# Generated deterministically by seda-macro-lef-normalizer-v1; recipe orfs-ng45-fakeram-metal3-coupledl2-pg-v1.
VERSION 5.8 ;
BUSBITCHARS "[]" ;
DIVIDERCHAR "/" ;

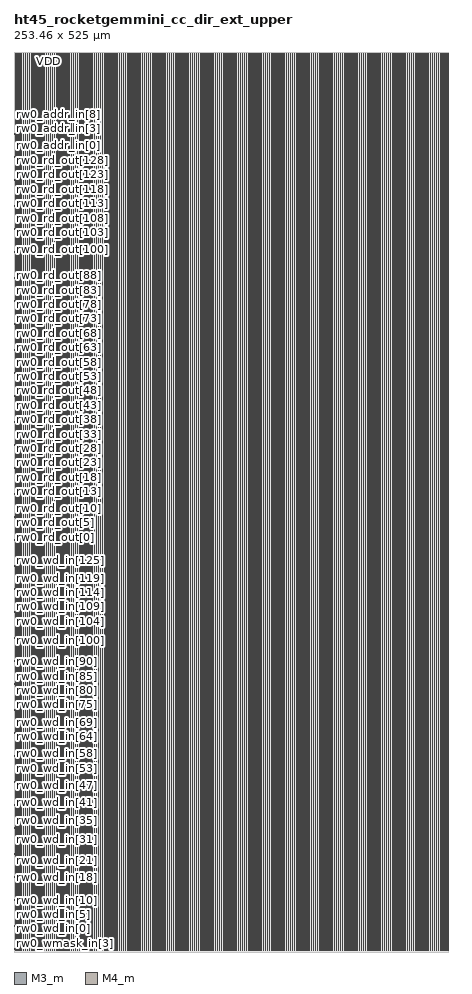
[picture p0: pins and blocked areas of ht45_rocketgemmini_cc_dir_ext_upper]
MACRO ht45_rocketgemmini_cc_dir_ext_upper
  FOREIGN ht45_rocketgemmini_cc_dir_ext_upper 0 0 ;
  CLASS COVER ;
  ORIGIN 0 0 ;
  SIZE 253.46 BY 525 ;
  SYMMETRY X Y R90 ;
  PIN rw0_wmask_in[0]
    DIRECTION INPUT ;
    USE SIGNAL ;
    SHAPE ABUTMENT ;
    PORT
      LAYER M3_m ;
      RECT 0 0.035 0.07 0.105 ;
    END
  END rw0_wmask_in[0]
  PIN rw0_wmask_in[1]
    DIRECTION INPUT ;
    USE SIGNAL ;
    SHAPE ABUTMENT ;
    PORT
      LAYER M3_m ;
      RECT 0 1.715 0.07 1.785 ;
    END
  END rw0_wmask_in[1]
  PIN rw0_wmask_in[2]
    DIRECTION INPUT ;
    USE SIGNAL ;
    SHAPE ABUTMENT ;
    PORT
      LAYER M3_m ;
      RECT 0 3.395 0.07 3.465 ;
    END
  END rw0_wmask_in[2]
  PIN rw0_wmask_in[3]
    DIRECTION INPUT ;
    USE SIGNAL ;
    SHAPE ABUTMENT ;
    PORT
      LAYER M3_m ;
      RECT 0 5.075 0.07 5.145 ;
    END
  END rw0_wmask_in[3]
  PIN rw0_wmask_in[4]
    DIRECTION INPUT ;
    USE SIGNAL ;
    SHAPE ABUTMENT ;
    PORT
      LAYER M3_m ;
      RECT 0 6.755 0.07 6.825 ;
    END
  END rw0_wmask_in[4]
  PIN rw0_wmask_in[5]
    DIRECTION INPUT ;
    USE SIGNAL ;
    SHAPE ABUTMENT ;
    PORT
      LAYER M3_m ;
      RECT 0 8.435 0.07 8.505 ;
    END
  END rw0_wmask_in[5]
  PIN rw0_wmask_in[6]
    DIRECTION INPUT ;
    USE SIGNAL ;
    SHAPE ABUTMENT ;
    PORT
      LAYER M3_m ;
      RECT 0 10.115 0.07 10.185 ;
    END
  END rw0_wmask_in[6]
  PIN rw0_wmask_in[7]
    DIRECTION INPUT ;
    USE SIGNAL ;
    SHAPE ABUTMENT ;
    PORT
      LAYER M3_m ;
      RECT 0 11.795 0.07 11.865 ;
    END
  END rw0_wmask_in[7]
  PIN rw0_wd_in[0]
    DIRECTION INPUT ;
    USE SIGNAL ;
    SHAPE ABUTMENT ;
    PORT
      LAYER M3_m ;
      RECT 0 13.475 0.07 13.545 ;
    END
  END rw0_wd_in[0]
  PIN rw0_wd_in[1]
    DIRECTION INPUT ;
    USE SIGNAL ;
    SHAPE ABUTMENT ;
    PORT
      LAYER M3_m ;
      RECT 0 15.155 0.07 15.225 ;
    END
  END rw0_wd_in[1]
  PIN rw0_wd_in[2]
    DIRECTION INPUT ;
    USE SIGNAL ;
    SHAPE ABUTMENT ;
    PORT
      LAYER M3_m ;
      RECT 0 16.835 0.07 16.905 ;
    END
  END rw0_wd_in[2]
  PIN rw0_wd_in[3]
    DIRECTION INPUT ;
    USE SIGNAL ;
    SHAPE ABUTMENT ;
    PORT
      LAYER M3_m ;
      RECT 0 18.515 0.07 18.585 ;
    END
  END rw0_wd_in[3]
  PIN rw0_wd_in[4]
    DIRECTION INPUT ;
    USE SIGNAL ;
    SHAPE ABUTMENT ;
    PORT
      LAYER M3_m ;
      RECT 0 20.195 0.07 20.265 ;
    END
  END rw0_wd_in[4]
  PIN rw0_wd_in[5]
    DIRECTION INPUT ;
    USE SIGNAL ;
    SHAPE ABUTMENT ;
    PORT
      LAYER M3_m ;
      RECT 0 21.875 0.07 21.945 ;
    END
  END rw0_wd_in[5]
  PIN rw0_wd_in[6]
    DIRECTION INPUT ;
    USE SIGNAL ;
    SHAPE ABUTMENT ;
    PORT
      LAYER M3_m ;
      RECT 0 23.555 0.07 23.625 ;
    END
  END rw0_wd_in[6]
  PIN rw0_wd_in[7]
    DIRECTION INPUT ;
    USE SIGNAL ;
    SHAPE ABUTMENT ;
    PORT
      LAYER M3_m ;
      RECT 0 25.235 0.07 25.305 ;
    END
  END rw0_wd_in[7]
  PIN rw0_wd_in[8]
    DIRECTION INPUT ;
    USE SIGNAL ;
    SHAPE ABUTMENT ;
    PORT
      LAYER M3_m ;
      RECT 0 26.915 0.07 26.985 ;
    END
  END rw0_wd_in[8]
  PIN rw0_wd_in[9]
    DIRECTION INPUT ;
    USE SIGNAL ;
    SHAPE ABUTMENT ;
    PORT
      LAYER M3_m ;
      RECT 0 28.595 0.07 28.665 ;
    END
  END rw0_wd_in[9]
  PIN rw0_wd_in[10]
    DIRECTION INPUT ;
    USE SIGNAL ;
    SHAPE ABUTMENT ;
    PORT
      LAYER M3_m ;
      RECT 0 30.275 0.07 30.345 ;
    END
  END rw0_wd_in[10]
  PIN rw0_wd_in[11]
    DIRECTION INPUT ;
    USE SIGNAL ;
    SHAPE ABUTMENT ;
    PORT
      LAYER M3_m ;
      RECT 0 31.955 0.07 32.025 ;
    END
  END rw0_wd_in[11]
  PIN rw0_wd_in[12]
    DIRECTION INPUT ;
    USE SIGNAL ;
    SHAPE ABUTMENT ;
    PORT
      LAYER M3_m ;
      RECT 0 33.635 0.07 33.705 ;
    END
  END rw0_wd_in[12]
  PIN rw0_wd_in[13]
    DIRECTION INPUT ;
    USE SIGNAL ;
    SHAPE ABUTMENT ;
    PORT
      LAYER M3_m ;
      RECT 0 35.315 0.07 35.385 ;
    END
  END rw0_wd_in[13]
  PIN rw0_wd_in[14]
    DIRECTION INPUT ;
    USE SIGNAL ;
    SHAPE ABUTMENT ;
    PORT
      LAYER M3_m ;
      RECT 0 36.995 0.07 37.065 ;
    END
  END rw0_wd_in[14]
  PIN rw0_wd_in[15]
    DIRECTION INPUT ;
    USE SIGNAL ;
    SHAPE ABUTMENT ;
    PORT
      LAYER M3_m ;
      RECT 0 38.675 0.07 38.745 ;
    END
  END rw0_wd_in[15]
  PIN rw0_wd_in[16]
    DIRECTION INPUT ;
    USE SIGNAL ;
    SHAPE ABUTMENT ;
    PORT
      LAYER M3_m ;
      RECT 0 40.355 0.07 40.425 ;
    END
  END rw0_wd_in[16]
  PIN rw0_wd_in[17]
    DIRECTION INPUT ;
    USE SIGNAL ;
    SHAPE ABUTMENT ;
    PORT
      LAYER M3_m ;
      RECT 0 42.035 0.07 42.105 ;
    END
  END rw0_wd_in[17]
  PIN rw0_wd_in[18]
    DIRECTION INPUT ;
    USE SIGNAL ;
    SHAPE ABUTMENT ;
    PORT
      LAYER M3_m ;
      RECT 0 43.715 0.07 43.785 ;
    END
  END rw0_wd_in[18]
  PIN rw0_wd_in[19]
    DIRECTION INPUT ;
    USE SIGNAL ;
    SHAPE ABUTMENT ;
    PORT
      LAYER M3_m ;
      RECT 0 45.395 0.07 45.465 ;
    END
  END rw0_wd_in[19]
  PIN rw0_wd_in[20]
    DIRECTION INPUT ;
    USE SIGNAL ;
    SHAPE ABUTMENT ;
    PORT
      LAYER M3_m ;
      RECT 0 47.075 0.07 47.145 ;
    END
  END rw0_wd_in[20]
  PIN rw0_wd_in[21]
    DIRECTION INPUT ;
    USE SIGNAL ;
    SHAPE ABUTMENT ;
    PORT
      LAYER M3_m ;
      RECT 0 48.755 0.07 48.825 ;
    END
  END rw0_wd_in[21]
  PIN rw0_wd_in[22]
    DIRECTION INPUT ;
    USE SIGNAL ;
    SHAPE ABUTMENT ;
    PORT
      LAYER M3_m ;
      RECT 0 50.435 0.07 50.505 ;
    END
  END rw0_wd_in[22]
  PIN rw0_wd_in[23]
    DIRECTION INPUT ;
    USE SIGNAL ;
    SHAPE ABUTMENT ;
    PORT
      LAYER M3_m ;
      RECT 0 52.115 0.07 52.185 ;
    END
  END rw0_wd_in[23]
  PIN rw0_wd_in[24]
    DIRECTION INPUT ;
    USE SIGNAL ;
    SHAPE ABUTMENT ;
    PORT
      LAYER M3_m ;
      RECT 0 53.795 0.07 53.865 ;
    END
  END rw0_wd_in[24]
  PIN rw0_wd_in[25]
    DIRECTION INPUT ;
    USE SIGNAL ;
    SHAPE ABUTMENT ;
    PORT
      LAYER M3_m ;
      RECT 0 55.475 0.07 55.545 ;
    END
  END rw0_wd_in[25]
  PIN rw0_wd_in[26]
    DIRECTION INPUT ;
    USE SIGNAL ;
    SHAPE ABUTMENT ;
    PORT
      LAYER M3_m ;
      RECT 0 57.155 0.07 57.225 ;
    END
  END rw0_wd_in[26]
  PIN rw0_wd_in[27]
    DIRECTION INPUT ;
    USE SIGNAL ;
    SHAPE ABUTMENT ;
    PORT
      LAYER M3_m ;
      RECT 0 58.835 0.07 58.905 ;
    END
  END rw0_wd_in[27]
  PIN rw0_wd_in[28]
    DIRECTION INPUT ;
    USE SIGNAL ;
    SHAPE ABUTMENT ;
    PORT
      LAYER M3_m ;
      RECT 0 60.515 0.07 60.585 ;
    END
  END rw0_wd_in[28]
  PIN rw0_wd_in[29]
    DIRECTION INPUT ;
    USE SIGNAL ;
    SHAPE ABUTMENT ;
    PORT
      LAYER M3_m ;
      RECT 0 62.195 0.07 62.265 ;
    END
  END rw0_wd_in[29]
  PIN rw0_wd_in[30]
    DIRECTION INPUT ;
    USE SIGNAL ;
    SHAPE ABUTMENT ;
    PORT
      LAYER M3_m ;
      RECT 0 63.875 0.07 63.945 ;
    END
  END rw0_wd_in[30]
  PIN rw0_wd_in[31]
    DIRECTION INPUT ;
    USE SIGNAL ;
    SHAPE ABUTMENT ;
    PORT
      LAYER M3_m ;
      RECT 0 65.555 0.07 65.625 ;
    END
  END rw0_wd_in[31]
  PIN rw0_wd_in[32]
    DIRECTION INPUT ;
    USE SIGNAL ;
    SHAPE ABUTMENT ;
    PORT
      LAYER M3_m ;
      RECT 0 67.235 0.07 67.305 ;
    END
  END rw0_wd_in[32]
  PIN rw0_wd_in[33]
    DIRECTION INPUT ;
    USE SIGNAL ;
    SHAPE ABUTMENT ;
    PORT
      LAYER M3_m ;
      RECT 0 68.915 0.07 68.985 ;
    END
  END rw0_wd_in[33]
  PIN rw0_wd_in[34]
    DIRECTION INPUT ;
    USE SIGNAL ;
    SHAPE ABUTMENT ;
    PORT
      LAYER M3_m ;
      RECT 0 70.595 0.07 70.665 ;
    END
  END rw0_wd_in[34]
  PIN rw0_wd_in[35]
    DIRECTION INPUT ;
    USE SIGNAL ;
    SHAPE ABUTMENT ;
    PORT
      LAYER M3_m ;
      RECT 0 72.275 0.07 72.345 ;
    END
  END rw0_wd_in[35]
  PIN rw0_wd_in[36]
    DIRECTION INPUT ;
    USE SIGNAL ;
    SHAPE ABUTMENT ;
    PORT
      LAYER M3_m ;
      RECT 0 73.955 0.07 74.025 ;
    END
  END rw0_wd_in[36]
  PIN rw0_wd_in[37]
    DIRECTION INPUT ;
    USE SIGNAL ;
    SHAPE ABUTMENT ;
    PORT
      LAYER M3_m ;
      RECT 0 75.635 0.07 75.705 ;
    END
  END rw0_wd_in[37]
  PIN rw0_wd_in[38]
    DIRECTION INPUT ;
    USE SIGNAL ;
    SHAPE ABUTMENT ;
    PORT
      LAYER M3_m ;
      RECT 0 77.315 0.07 77.385 ;
    END
  END rw0_wd_in[38]
  PIN rw0_wd_in[39]
    DIRECTION INPUT ;
    USE SIGNAL ;
    SHAPE ABUTMENT ;
    PORT
      LAYER M3_m ;
      RECT 0 78.995 0.07 79.065 ;
    END
  END rw0_wd_in[39]
  PIN rw0_wd_in[40]
    DIRECTION INPUT ;
    USE SIGNAL ;
    SHAPE ABUTMENT ;
    PORT
      LAYER M3_m ;
      RECT 0 80.675 0.07 80.745 ;
    END
  END rw0_wd_in[40]
  PIN rw0_wd_in[41]
    DIRECTION INPUT ;
    USE SIGNAL ;
    SHAPE ABUTMENT ;
    PORT
      LAYER M3_m ;
      RECT 0 82.355 0.07 82.425 ;
    END
  END rw0_wd_in[41]
  PIN rw0_wd_in[42]
    DIRECTION INPUT ;
    USE SIGNAL ;
    SHAPE ABUTMENT ;
    PORT
      LAYER M3_m ;
      RECT 0 84.035 0.07 84.105 ;
    END
  END rw0_wd_in[42]
  PIN rw0_wd_in[43]
    DIRECTION INPUT ;
    USE SIGNAL ;
    SHAPE ABUTMENT ;
    PORT
      LAYER M3_m ;
      RECT 0 85.715 0.07 85.785 ;
    END
  END rw0_wd_in[43]
  PIN rw0_wd_in[44]
    DIRECTION INPUT ;
    USE SIGNAL ;
    SHAPE ABUTMENT ;
    PORT
      LAYER M3_m ;
      RECT 0 87.395 0.07 87.465 ;
    END
  END rw0_wd_in[44]
  PIN rw0_wd_in[45]
    DIRECTION INPUT ;
    USE SIGNAL ;
    SHAPE ABUTMENT ;
    PORT
      LAYER M3_m ;
      RECT 0 89.075 0.07 89.145 ;
    END
  END rw0_wd_in[45]
  PIN rw0_wd_in[46]
    DIRECTION INPUT ;
    USE SIGNAL ;
    SHAPE ABUTMENT ;
    PORT
      LAYER M3_m ;
      RECT 0 90.755 0.07 90.825 ;
    END
  END rw0_wd_in[46]
  PIN rw0_wd_in[47]
    DIRECTION INPUT ;
    USE SIGNAL ;
    SHAPE ABUTMENT ;
    PORT
      LAYER M3_m ;
      RECT 0 92.435 0.07 92.505 ;
    END
  END rw0_wd_in[47]
  PIN rw0_wd_in[48]
    DIRECTION INPUT ;
    USE SIGNAL ;
    SHAPE ABUTMENT ;
    PORT
      LAYER M3_m ;
      RECT 0 94.115 0.07 94.185 ;
    END
  END rw0_wd_in[48]
  PIN rw0_wd_in[49]
    DIRECTION INPUT ;
    USE SIGNAL ;
    SHAPE ABUTMENT ;
    PORT
      LAYER M3_m ;
      RECT 0 95.795 0.07 95.865 ;
    END
  END rw0_wd_in[49]
  PIN rw0_wd_in[50]
    DIRECTION INPUT ;
    USE SIGNAL ;
    SHAPE ABUTMENT ;
    PORT
      LAYER M3_m ;
      RECT 0 97.475 0.07 97.545 ;
    END
  END rw0_wd_in[50]
  PIN rw0_wd_in[51]
    DIRECTION INPUT ;
    USE SIGNAL ;
    SHAPE ABUTMENT ;
    PORT
      LAYER M3_m ;
      RECT 0 99.155 0.07 99.225 ;
    END
  END rw0_wd_in[51]
  PIN rw0_wd_in[52]
    DIRECTION INPUT ;
    USE SIGNAL ;
    SHAPE ABUTMENT ;
    PORT
      LAYER M3_m ;
      RECT 0 100.835 0.07 100.905 ;
    END
  END rw0_wd_in[52]
  PIN rw0_wd_in[53]
    DIRECTION INPUT ;
    USE SIGNAL ;
    SHAPE ABUTMENT ;
    PORT
      LAYER M3_m ;
      RECT 0 102.515 0.07 102.585 ;
    END
  END rw0_wd_in[53]
  PIN rw0_wd_in[54]
    DIRECTION INPUT ;
    USE SIGNAL ;
    SHAPE ABUTMENT ;
    PORT
      LAYER M3_m ;
      RECT 0 104.195 0.07 104.265 ;
    END
  END rw0_wd_in[54]
  PIN rw0_wd_in[55]
    DIRECTION INPUT ;
    USE SIGNAL ;
    SHAPE ABUTMENT ;
    PORT
      LAYER M3_m ;
      RECT 0 105.875 0.07 105.945 ;
    END
  END rw0_wd_in[55]
  PIN rw0_wd_in[56]
    DIRECTION INPUT ;
    USE SIGNAL ;
    SHAPE ABUTMENT ;
    PORT
      LAYER M3_m ;
      RECT 0 107.555 0.07 107.625 ;
    END
  END rw0_wd_in[56]
  PIN rw0_wd_in[57]
    DIRECTION INPUT ;
    USE SIGNAL ;
    SHAPE ABUTMENT ;
    PORT
      LAYER M3_m ;
      RECT 0 109.235 0.07 109.305 ;
    END
  END rw0_wd_in[57]
  PIN rw0_wd_in[58]
    DIRECTION INPUT ;
    USE SIGNAL ;
    SHAPE ABUTMENT ;
    PORT
      LAYER M3_m ;
      RECT 0 110.915 0.07 110.985 ;
    END
  END rw0_wd_in[58]
  PIN rw0_wd_in[59]
    DIRECTION INPUT ;
    USE SIGNAL ;
    SHAPE ABUTMENT ;
    PORT
      LAYER M3_m ;
      RECT 0 112.595 0.07 112.665 ;
    END
  END rw0_wd_in[59]
  PIN rw0_wd_in[60]
    DIRECTION INPUT ;
    USE SIGNAL ;
    SHAPE ABUTMENT ;
    PORT
      LAYER M3_m ;
      RECT 0 114.275 0.07 114.345 ;
    END
  END rw0_wd_in[60]
  PIN rw0_wd_in[61]
    DIRECTION INPUT ;
    USE SIGNAL ;
    SHAPE ABUTMENT ;
    PORT
      LAYER M3_m ;
      RECT 0 115.955 0.07 116.025 ;
    END
  END rw0_wd_in[61]
  PIN rw0_wd_in[62]
    DIRECTION INPUT ;
    USE SIGNAL ;
    SHAPE ABUTMENT ;
    PORT
      LAYER M3_m ;
      RECT 0 117.635 0.07 117.705 ;
    END
  END rw0_wd_in[62]
  PIN rw0_wd_in[63]
    DIRECTION INPUT ;
    USE SIGNAL ;
    SHAPE ABUTMENT ;
    PORT
      LAYER M3_m ;
      RECT 0 119.315 0.07 119.385 ;
    END
  END rw0_wd_in[63]
  PIN rw0_wd_in[64]
    DIRECTION INPUT ;
    USE SIGNAL ;
    SHAPE ABUTMENT ;
    PORT
      LAYER M3_m ;
      RECT 0 120.995 0.07 121.065 ;
    END
  END rw0_wd_in[64]
  PIN rw0_wd_in[65]
    DIRECTION INPUT ;
    USE SIGNAL ;
    SHAPE ABUTMENT ;
    PORT
      LAYER M3_m ;
      RECT 0 122.675 0.07 122.745 ;
    END
  END rw0_wd_in[65]
  PIN rw0_wd_in[66]
    DIRECTION INPUT ;
    USE SIGNAL ;
    SHAPE ABUTMENT ;
    PORT
      LAYER M3_m ;
      RECT 0 124.355 0.07 124.425 ;
    END
  END rw0_wd_in[66]
  PIN rw0_wd_in[67]
    DIRECTION INPUT ;
    USE SIGNAL ;
    SHAPE ABUTMENT ;
    PORT
      LAYER M3_m ;
      RECT 0 126.035 0.07 126.105 ;
    END
  END rw0_wd_in[67]
  PIN rw0_wd_in[68]
    DIRECTION INPUT ;
    USE SIGNAL ;
    SHAPE ABUTMENT ;
    PORT
      LAYER M3_m ;
      RECT 0 127.715 0.07 127.785 ;
    END
  END rw0_wd_in[68]
  PIN rw0_wd_in[69]
    DIRECTION INPUT ;
    USE SIGNAL ;
    SHAPE ABUTMENT ;
    PORT
      LAYER M3_m ;
      RECT 0 129.395 0.07 129.465 ;
    END
  END rw0_wd_in[69]
  PIN rw0_wd_in[70]
    DIRECTION INPUT ;
    USE SIGNAL ;
    SHAPE ABUTMENT ;
    PORT
      LAYER M3_m ;
      RECT 0 131.075 0.07 131.145 ;
    END
  END rw0_wd_in[70]
  PIN rw0_wd_in[71]
    DIRECTION INPUT ;
    USE SIGNAL ;
    SHAPE ABUTMENT ;
    PORT
      LAYER M3_m ;
      RECT 0 132.755 0.07 132.825 ;
    END
  END rw0_wd_in[71]
  PIN rw0_wd_in[72]
    DIRECTION INPUT ;
    USE SIGNAL ;
    SHAPE ABUTMENT ;
    PORT
      LAYER M3_m ;
      RECT 0 134.435 0.07 134.505 ;
    END
  END rw0_wd_in[72]
  PIN rw0_wd_in[73]
    DIRECTION INPUT ;
    USE SIGNAL ;
    SHAPE ABUTMENT ;
    PORT
      LAYER M3_m ;
      RECT 0 136.115 0.07 136.185 ;
    END
  END rw0_wd_in[73]
  PIN rw0_wd_in[74]
    DIRECTION INPUT ;
    USE SIGNAL ;
    SHAPE ABUTMENT ;
    PORT
      LAYER M3_m ;
      RECT 0 137.795 0.07 137.865 ;
    END
  END rw0_wd_in[74]
  PIN rw0_wd_in[75]
    DIRECTION INPUT ;
    USE SIGNAL ;
    SHAPE ABUTMENT ;
    PORT
      LAYER M3_m ;
      RECT 0 139.475 0.07 139.545 ;
    END
  END rw0_wd_in[75]
  PIN rw0_wd_in[76]
    DIRECTION INPUT ;
    USE SIGNAL ;
    SHAPE ABUTMENT ;
    PORT
      LAYER M3_m ;
      RECT 0 141.155 0.07 141.225 ;
    END
  END rw0_wd_in[76]
  PIN rw0_wd_in[77]
    DIRECTION INPUT ;
    USE SIGNAL ;
    SHAPE ABUTMENT ;
    PORT
      LAYER M3_m ;
      RECT 0 142.835 0.07 142.905 ;
    END
  END rw0_wd_in[77]
  PIN rw0_wd_in[78]
    DIRECTION INPUT ;
    USE SIGNAL ;
    SHAPE ABUTMENT ;
    PORT
      LAYER M3_m ;
      RECT 0 144.515 0.07 144.585 ;
    END
  END rw0_wd_in[78]
  PIN rw0_wd_in[79]
    DIRECTION INPUT ;
    USE SIGNAL ;
    SHAPE ABUTMENT ;
    PORT
      LAYER M3_m ;
      RECT 0 146.195 0.07 146.265 ;
    END
  END rw0_wd_in[79]
  PIN rw0_wd_in[80]
    DIRECTION INPUT ;
    USE SIGNAL ;
    SHAPE ABUTMENT ;
    PORT
      LAYER M3_m ;
      RECT 0 147.875 0.07 147.945 ;
    END
  END rw0_wd_in[80]
  PIN rw0_wd_in[81]
    DIRECTION INPUT ;
    USE SIGNAL ;
    SHAPE ABUTMENT ;
    PORT
      LAYER M3_m ;
      RECT 0 149.555 0.07 149.625 ;
    END
  END rw0_wd_in[81]
  PIN rw0_wd_in[82]
    DIRECTION INPUT ;
    USE SIGNAL ;
    SHAPE ABUTMENT ;
    PORT
      LAYER M3_m ;
      RECT 0 151.235 0.07 151.305 ;
    END
  END rw0_wd_in[82]
  PIN rw0_wd_in[83]
    DIRECTION INPUT ;
    USE SIGNAL ;
    SHAPE ABUTMENT ;
    PORT
      LAYER M3_m ;
      RECT 0 152.915 0.07 152.985 ;
    END
  END rw0_wd_in[83]
  PIN rw0_wd_in[84]
    DIRECTION INPUT ;
    USE SIGNAL ;
    SHAPE ABUTMENT ;
    PORT
      LAYER M3_m ;
      RECT 0 154.595 0.07 154.665 ;
    END
  END rw0_wd_in[84]
  PIN rw0_wd_in[85]
    DIRECTION INPUT ;
    USE SIGNAL ;
    SHAPE ABUTMENT ;
    PORT
      LAYER M3_m ;
      RECT 0 156.275 0.07 156.345 ;
    END
  END rw0_wd_in[85]
  PIN rw0_wd_in[86]
    DIRECTION INPUT ;
    USE SIGNAL ;
    SHAPE ABUTMENT ;
    PORT
      LAYER M3_m ;
      RECT 0 157.955 0.07 158.025 ;
    END
  END rw0_wd_in[86]
  PIN rw0_wd_in[87]
    DIRECTION INPUT ;
    USE SIGNAL ;
    SHAPE ABUTMENT ;
    PORT
      LAYER M3_m ;
      RECT 0 159.635 0.07 159.705 ;
    END
  END rw0_wd_in[87]
  PIN rw0_wd_in[88]
    DIRECTION INPUT ;
    USE SIGNAL ;
    SHAPE ABUTMENT ;
    PORT
      LAYER M3_m ;
      RECT 0 161.315 0.07 161.385 ;
    END
  END rw0_wd_in[88]
  PIN rw0_wd_in[89]
    DIRECTION INPUT ;
    USE SIGNAL ;
    SHAPE ABUTMENT ;
    PORT
      LAYER M3_m ;
      RECT 0 162.995 0.07 163.065 ;
    END
  END rw0_wd_in[89]
  PIN rw0_wd_in[90]
    DIRECTION INPUT ;
    USE SIGNAL ;
    SHAPE ABUTMENT ;
    PORT
      LAYER M3_m ;
      RECT 0 164.675 0.07 164.745 ;
    END
  END rw0_wd_in[90]
  PIN rw0_wd_in[91]
    DIRECTION INPUT ;
    USE SIGNAL ;
    SHAPE ABUTMENT ;
    PORT
      LAYER M3_m ;
      RECT 0 166.355 0.07 166.425 ;
    END
  END rw0_wd_in[91]
  PIN rw0_wd_in[92]
    DIRECTION INPUT ;
    USE SIGNAL ;
    SHAPE ABUTMENT ;
    PORT
      LAYER M3_m ;
      RECT 0 168.035 0.07 168.105 ;
    END
  END rw0_wd_in[92]
  PIN rw0_wd_in[93]
    DIRECTION INPUT ;
    USE SIGNAL ;
    SHAPE ABUTMENT ;
    PORT
      LAYER M3_m ;
      RECT 0 169.715 0.07 169.785 ;
    END
  END rw0_wd_in[93]
  PIN rw0_wd_in[94]
    DIRECTION INPUT ;
    USE SIGNAL ;
    SHAPE ABUTMENT ;
    PORT
      LAYER M3_m ;
      RECT 0 171.395 0.07 171.465 ;
    END
  END rw0_wd_in[94]
  PIN rw0_wd_in[95]
    DIRECTION INPUT ;
    USE SIGNAL ;
    SHAPE ABUTMENT ;
    PORT
      LAYER M3_m ;
      RECT 0 173.075 0.07 173.145 ;
    END
  END rw0_wd_in[95]
  PIN rw0_wd_in[96]
    DIRECTION INPUT ;
    USE SIGNAL ;
    SHAPE ABUTMENT ;
    PORT
      LAYER M3_m ;
      RECT 0 174.755 0.07 174.825 ;
    END
  END rw0_wd_in[96]
  PIN rw0_wd_in[97]
    DIRECTION INPUT ;
    USE SIGNAL ;
    SHAPE ABUTMENT ;
    PORT
      LAYER M3_m ;
      RECT 0 176.435 0.07 176.505 ;
    END
  END rw0_wd_in[97]
  PIN rw0_wd_in[98]
    DIRECTION INPUT ;
    USE SIGNAL ;
    SHAPE ABUTMENT ;
    PORT
      LAYER M3_m ;
      RECT 0 178.115 0.07 178.185 ;
    END
  END rw0_wd_in[98]
  PIN rw0_wd_in[99]
    DIRECTION INPUT ;
    USE SIGNAL ;
    SHAPE ABUTMENT ;
    PORT
      LAYER M3_m ;
      RECT 0 179.795 0.07 179.865 ;
    END
  END rw0_wd_in[99]
  PIN rw0_wd_in[100]
    DIRECTION INPUT ;
    USE SIGNAL ;
    SHAPE ABUTMENT ;
    PORT
      LAYER M3_m ;
      RECT 0 181.475 0.07 181.545 ;
    END
  END rw0_wd_in[100]
  PIN rw0_wd_in[101]
    DIRECTION INPUT ;
    USE SIGNAL ;
    SHAPE ABUTMENT ;
    PORT
      LAYER M3_m ;
      RECT 0 183.155 0.07 183.225 ;
    END
  END rw0_wd_in[101]
  PIN rw0_wd_in[102]
    DIRECTION INPUT ;
    USE SIGNAL ;
    SHAPE ABUTMENT ;
    PORT
      LAYER M3_m ;
      RECT 0 184.835 0.07 184.905 ;
    END
  END rw0_wd_in[102]
  PIN rw0_wd_in[103]
    DIRECTION INPUT ;
    USE SIGNAL ;
    SHAPE ABUTMENT ;
    PORT
      LAYER M3_m ;
      RECT 0 186.515 0.07 186.585 ;
    END
  END rw0_wd_in[103]
  PIN rw0_wd_in[104]
    DIRECTION INPUT ;
    USE SIGNAL ;
    SHAPE ABUTMENT ;
    PORT
      LAYER M3_m ;
      RECT 0 188.195 0.07 188.265 ;
    END
  END rw0_wd_in[104]
  PIN rw0_wd_in[105]
    DIRECTION INPUT ;
    USE SIGNAL ;
    SHAPE ABUTMENT ;
    PORT
      LAYER M3_m ;
      RECT 0 189.875 0.07 189.945 ;
    END
  END rw0_wd_in[105]
  PIN rw0_wd_in[106]
    DIRECTION INPUT ;
    USE SIGNAL ;
    SHAPE ABUTMENT ;
    PORT
      LAYER M3_m ;
      RECT 0 191.555 0.07 191.625 ;
    END
  END rw0_wd_in[106]
  PIN rw0_wd_in[107]
    DIRECTION INPUT ;
    USE SIGNAL ;
    SHAPE ABUTMENT ;
    PORT
      LAYER M3_m ;
      RECT 0 193.235 0.07 193.305 ;
    END
  END rw0_wd_in[107]
  PIN rw0_wd_in[108]
    DIRECTION INPUT ;
    USE SIGNAL ;
    SHAPE ABUTMENT ;
    PORT
      LAYER M3_m ;
      RECT 0 194.915 0.07 194.985 ;
    END
  END rw0_wd_in[108]
  PIN rw0_wd_in[109]
    DIRECTION INPUT ;
    USE SIGNAL ;
    SHAPE ABUTMENT ;
    PORT
      LAYER M3_m ;
      RECT 0 196.595 0.07 196.665 ;
    END
  END rw0_wd_in[109]
  PIN rw0_wd_in[110]
    DIRECTION INPUT ;
    USE SIGNAL ;
    SHAPE ABUTMENT ;
    PORT
      LAYER M3_m ;
      RECT 0 198.275 0.07 198.345 ;
    END
  END rw0_wd_in[110]
  PIN rw0_wd_in[111]
    DIRECTION INPUT ;
    USE SIGNAL ;
    SHAPE ABUTMENT ;
    PORT
      LAYER M3_m ;
      RECT 0 199.955 0.07 200.025 ;
    END
  END rw0_wd_in[111]
  PIN rw0_wd_in[112]
    DIRECTION INPUT ;
    USE SIGNAL ;
    SHAPE ABUTMENT ;
    PORT
      LAYER M3_m ;
      RECT 0 201.635 0.07 201.705 ;
    END
  END rw0_wd_in[112]
  PIN rw0_wd_in[113]
    DIRECTION INPUT ;
    USE SIGNAL ;
    SHAPE ABUTMENT ;
    PORT
      LAYER M3_m ;
      RECT 0 203.315 0.07 203.385 ;
    END
  END rw0_wd_in[113]
  PIN rw0_wd_in[114]
    DIRECTION INPUT ;
    USE SIGNAL ;
    SHAPE ABUTMENT ;
    PORT
      LAYER M3_m ;
      RECT 0 204.995 0.07 205.065 ;
    END
  END rw0_wd_in[114]
  PIN rw0_wd_in[115]
    DIRECTION INPUT ;
    USE SIGNAL ;
    SHAPE ABUTMENT ;
    PORT
      LAYER M3_m ;
      RECT 0 206.675 0.07 206.745 ;
    END
  END rw0_wd_in[115]
  PIN rw0_wd_in[116]
    DIRECTION INPUT ;
    USE SIGNAL ;
    SHAPE ABUTMENT ;
    PORT
      LAYER M3_m ;
      RECT 0 208.355 0.07 208.425 ;
    END
  END rw0_wd_in[116]
  PIN rw0_wd_in[117]
    DIRECTION INPUT ;
    USE SIGNAL ;
    SHAPE ABUTMENT ;
    PORT
      LAYER M3_m ;
      RECT 0 210.035 0.07 210.105 ;
    END
  END rw0_wd_in[117]
  PIN rw0_wd_in[118]
    DIRECTION INPUT ;
    USE SIGNAL ;
    SHAPE ABUTMENT ;
    PORT
      LAYER M3_m ;
      RECT 0 211.715 0.07 211.785 ;
    END
  END rw0_wd_in[118]
  PIN rw0_wd_in[119]
    DIRECTION INPUT ;
    USE SIGNAL ;
    SHAPE ABUTMENT ;
    PORT
      LAYER M3_m ;
      RECT 0 213.395 0.07 213.465 ;
    END
  END rw0_wd_in[119]
  PIN rw0_wd_in[120]
    DIRECTION INPUT ;
    USE SIGNAL ;
    SHAPE ABUTMENT ;
    PORT
      LAYER M3_m ;
      RECT 0 215.075 0.07 215.145 ;
    END
  END rw0_wd_in[120]
  PIN rw0_wd_in[121]
    DIRECTION INPUT ;
    USE SIGNAL ;
    SHAPE ABUTMENT ;
    PORT
      LAYER M3_m ;
      RECT 0 216.755 0.07 216.825 ;
    END
  END rw0_wd_in[121]
  PIN rw0_wd_in[122]
    DIRECTION INPUT ;
    USE SIGNAL ;
    SHAPE ABUTMENT ;
    PORT
      LAYER M3_m ;
      RECT 0 218.435 0.07 218.505 ;
    END
  END rw0_wd_in[122]
  PIN rw0_wd_in[123]
    DIRECTION INPUT ;
    USE SIGNAL ;
    SHAPE ABUTMENT ;
    PORT
      LAYER M3_m ;
      RECT 0 220.115 0.07 220.185 ;
    END
  END rw0_wd_in[123]
  PIN rw0_wd_in[124]
    DIRECTION INPUT ;
    USE SIGNAL ;
    SHAPE ABUTMENT ;
    PORT
      LAYER M3_m ;
      RECT 0 221.795 0.07 221.865 ;
    END
  END rw0_wd_in[124]
  PIN rw0_wd_in[125]
    DIRECTION INPUT ;
    USE SIGNAL ;
    SHAPE ABUTMENT ;
    PORT
      LAYER M3_m ;
      RECT 0 223.475 0.07 223.545 ;
    END
  END rw0_wd_in[125]
  PIN rw0_wd_in[126]
    DIRECTION INPUT ;
    USE SIGNAL ;
    SHAPE ABUTMENT ;
    PORT
      LAYER M3_m ;
      RECT 0 225.155 0.07 225.225 ;
    END
  END rw0_wd_in[126]
  PIN rw0_wd_in[127]
    DIRECTION INPUT ;
    USE SIGNAL ;
    SHAPE ABUTMENT ;
    PORT
      LAYER M3_m ;
      RECT 0 226.835 0.07 226.905 ;
    END
  END rw0_wd_in[127]
  PIN rw0_wd_in[128]
    DIRECTION INPUT ;
    USE SIGNAL ;
    SHAPE ABUTMENT ;
    PORT
      LAYER M3_m ;
      RECT 0 228.515 0.07 228.585 ;
    END
  END rw0_wd_in[128]
  PIN rw0_wd_in[129]
    DIRECTION INPUT ;
    USE SIGNAL ;
    SHAPE ABUTMENT ;
    PORT
      LAYER M3_m ;
      RECT 0 230.195 0.07 230.265 ;
    END
  END rw0_wd_in[129]
  PIN rw0_wd_in[130]
    DIRECTION INPUT ;
    USE SIGNAL ;
    SHAPE ABUTMENT ;
    PORT
      LAYER M3_m ;
      RECT 0 231.875 0.07 231.945 ;
    END
  END rw0_wd_in[130]
  PIN rw0_wd_in[131]
    DIRECTION INPUT ;
    USE SIGNAL ;
    SHAPE ABUTMENT ;
    PORT
      LAYER M3_m ;
      RECT 0 233.555 0.07 233.625 ;
    END
  END rw0_wd_in[131]
  PIN rw0_wd_in[132]
    DIRECTION INPUT ;
    USE SIGNAL ;
    SHAPE ABUTMENT ;
    PORT
      LAYER M3_m ;
      RECT 0 235.235 0.07 235.305 ;
    END
  END rw0_wd_in[132]
  PIN rw0_wd_in[133]
    DIRECTION INPUT ;
    USE SIGNAL ;
    SHAPE ABUTMENT ;
    PORT
      LAYER M3_m ;
      RECT 0 236.915 0.07 236.985 ;
    END
  END rw0_wd_in[133]
  PIN rw0_wd_in[134]
    DIRECTION INPUT ;
    USE SIGNAL ;
    SHAPE ABUTMENT ;
    PORT
      LAYER M3_m ;
      RECT 0 238.595 0.07 238.665 ;
    END
  END rw0_wd_in[134]
  PIN rw0_wd_in[135]
    DIRECTION INPUT ;
    USE SIGNAL ;
    SHAPE ABUTMENT ;
    PORT
      LAYER M3_m ;
      RECT 0 240.275 0.07 240.345 ;
    END
  END rw0_wd_in[135]
  PIN rw0_rd_out[0]
    DIRECTION OUTPUT ;
    USE SIGNAL ;
    SHAPE ABUTMENT ;
    PORT
      LAYER M3_m ;
      RECT 0 241.955 0.07 242.025 ;
    END
  END rw0_rd_out[0]
  PIN rw0_rd_out[1]
    DIRECTION OUTPUT ;
    USE SIGNAL ;
    SHAPE ABUTMENT ;
    PORT
      LAYER M3_m ;
      RECT 0 243.635 0.07 243.705 ;
    END
  END rw0_rd_out[1]
  PIN rw0_rd_out[2]
    DIRECTION OUTPUT ;
    USE SIGNAL ;
    SHAPE ABUTMENT ;
    PORT
      LAYER M3_m ;
      RECT 0 245.315 0.07 245.385 ;
    END
  END rw0_rd_out[2]
  PIN rw0_rd_out[3]
    DIRECTION OUTPUT ;
    USE SIGNAL ;
    SHAPE ABUTMENT ;
    PORT
      LAYER M3_m ;
      RECT 0 246.995 0.07 247.065 ;
    END
  END rw0_rd_out[3]
  PIN rw0_rd_out[4]
    DIRECTION OUTPUT ;
    USE SIGNAL ;
    SHAPE ABUTMENT ;
    PORT
      LAYER M3_m ;
      RECT 0 248.675 0.07 248.745 ;
    END
  END rw0_rd_out[4]
  PIN rw0_rd_out[5]
    DIRECTION OUTPUT ;
    USE SIGNAL ;
    SHAPE ABUTMENT ;
    PORT
      LAYER M3_m ;
      RECT 0 250.355 0.07 250.425 ;
    END
  END rw0_rd_out[5]
  PIN rw0_rd_out[6]
    DIRECTION OUTPUT ;
    USE SIGNAL ;
    SHAPE ABUTMENT ;
    PORT
      LAYER M3_m ;
      RECT 0 252.035 0.07 252.105 ;
    END
  END rw0_rd_out[6]
  PIN rw0_rd_out[7]
    DIRECTION OUTPUT ;
    USE SIGNAL ;
    SHAPE ABUTMENT ;
    PORT
      LAYER M3_m ;
      RECT 0 253.715 0.07 253.785 ;
    END
  END rw0_rd_out[7]
  PIN rw0_rd_out[8]
    DIRECTION OUTPUT ;
    USE SIGNAL ;
    SHAPE ABUTMENT ;
    PORT
      LAYER M3_m ;
      RECT 0 255.395 0.07 255.465 ;
    END
  END rw0_rd_out[8]
  PIN rw0_rd_out[9]
    DIRECTION OUTPUT ;
    USE SIGNAL ;
    SHAPE ABUTMENT ;
    PORT
      LAYER M3_m ;
      RECT 0 257.075 0.07 257.145 ;
    END
  END rw0_rd_out[9]
  PIN rw0_rd_out[10]
    DIRECTION OUTPUT ;
    USE SIGNAL ;
    SHAPE ABUTMENT ;
    PORT
      LAYER M3_m ;
      RECT 0 258.755 0.07 258.825 ;
    END
  END rw0_rd_out[10]
  PIN rw0_rd_out[11]
    DIRECTION OUTPUT ;
    USE SIGNAL ;
    SHAPE ABUTMENT ;
    PORT
      LAYER M3_m ;
      RECT 0 260.435 0.07 260.505 ;
    END
  END rw0_rd_out[11]
  PIN rw0_rd_out[12]
    DIRECTION OUTPUT ;
    USE SIGNAL ;
    SHAPE ABUTMENT ;
    PORT
      LAYER M3_m ;
      RECT 0 262.115 0.07 262.185 ;
    END
  END rw0_rd_out[12]
  PIN rw0_rd_out[13]
    DIRECTION OUTPUT ;
    USE SIGNAL ;
    SHAPE ABUTMENT ;
    PORT
      LAYER M3_m ;
      RECT 0 263.795 0.07 263.865 ;
    END
  END rw0_rd_out[13]
  PIN rw0_rd_out[14]
    DIRECTION OUTPUT ;
    USE SIGNAL ;
    SHAPE ABUTMENT ;
    PORT
      LAYER M3_m ;
      RECT 0 265.475 0.07 265.545 ;
    END
  END rw0_rd_out[14]
  PIN rw0_rd_out[15]
    DIRECTION OUTPUT ;
    USE SIGNAL ;
    SHAPE ABUTMENT ;
    PORT
      LAYER M3_m ;
      RECT 0 267.155 0.07 267.225 ;
    END
  END rw0_rd_out[15]
  PIN rw0_rd_out[16]
    DIRECTION OUTPUT ;
    USE SIGNAL ;
    SHAPE ABUTMENT ;
    PORT
      LAYER M3_m ;
      RECT 0 268.835 0.07 268.905 ;
    END
  END rw0_rd_out[16]
  PIN rw0_rd_out[17]
    DIRECTION OUTPUT ;
    USE SIGNAL ;
    SHAPE ABUTMENT ;
    PORT
      LAYER M3_m ;
      RECT 0 270.515 0.07 270.585 ;
    END
  END rw0_rd_out[17]
  PIN rw0_rd_out[18]
    DIRECTION OUTPUT ;
    USE SIGNAL ;
    SHAPE ABUTMENT ;
    PORT
      LAYER M3_m ;
      RECT 0 272.195 0.07 272.265 ;
    END
  END rw0_rd_out[18]
  PIN rw0_rd_out[19]
    DIRECTION OUTPUT ;
    USE SIGNAL ;
    SHAPE ABUTMENT ;
    PORT
      LAYER M3_m ;
      RECT 0 273.875 0.07 273.945 ;
    END
  END rw0_rd_out[19]
  PIN rw0_rd_out[20]
    DIRECTION OUTPUT ;
    USE SIGNAL ;
    SHAPE ABUTMENT ;
    PORT
      LAYER M3_m ;
      RECT 0 275.555 0.07 275.625 ;
    END
  END rw0_rd_out[20]
  PIN rw0_rd_out[21]
    DIRECTION OUTPUT ;
    USE SIGNAL ;
    SHAPE ABUTMENT ;
    PORT
      LAYER M3_m ;
      RECT 0 277.235 0.07 277.305 ;
    END
  END rw0_rd_out[21]
  PIN rw0_rd_out[22]
    DIRECTION OUTPUT ;
    USE SIGNAL ;
    SHAPE ABUTMENT ;
    PORT
      LAYER M3_m ;
      RECT 0 278.915 0.07 278.985 ;
    END
  END rw0_rd_out[22]
  PIN rw0_rd_out[23]
    DIRECTION OUTPUT ;
    USE SIGNAL ;
    SHAPE ABUTMENT ;
    PORT
      LAYER M3_m ;
      RECT 0 280.595 0.07 280.665 ;
    END
  END rw0_rd_out[23]
  PIN rw0_rd_out[24]
    DIRECTION OUTPUT ;
    USE SIGNAL ;
    SHAPE ABUTMENT ;
    PORT
      LAYER M3_m ;
      RECT 0 282.275 0.07 282.345 ;
    END
  END rw0_rd_out[24]
  PIN rw0_rd_out[25]
    DIRECTION OUTPUT ;
    USE SIGNAL ;
    SHAPE ABUTMENT ;
    PORT
      LAYER M3_m ;
      RECT 0 283.955 0.07 284.025 ;
    END
  END rw0_rd_out[25]
  PIN rw0_rd_out[26]
    DIRECTION OUTPUT ;
    USE SIGNAL ;
    SHAPE ABUTMENT ;
    PORT
      LAYER M3_m ;
      RECT 0 285.635 0.07 285.705 ;
    END
  END rw0_rd_out[26]
  PIN rw0_rd_out[27]
    DIRECTION OUTPUT ;
    USE SIGNAL ;
    SHAPE ABUTMENT ;
    PORT
      LAYER M3_m ;
      RECT 0 287.315 0.07 287.385 ;
    END
  END rw0_rd_out[27]
  PIN rw0_rd_out[28]
    DIRECTION OUTPUT ;
    USE SIGNAL ;
    SHAPE ABUTMENT ;
    PORT
      LAYER M3_m ;
      RECT 0 288.995 0.07 289.065 ;
    END
  END rw0_rd_out[28]
  PIN rw0_rd_out[29]
    DIRECTION OUTPUT ;
    USE SIGNAL ;
    SHAPE ABUTMENT ;
    PORT
      LAYER M3_m ;
      RECT 0 290.675 0.07 290.745 ;
    END
  END rw0_rd_out[29]
  PIN rw0_rd_out[30]
    DIRECTION OUTPUT ;
    USE SIGNAL ;
    SHAPE ABUTMENT ;
    PORT
      LAYER M3_m ;
      RECT 0 292.355 0.07 292.425 ;
    END
  END rw0_rd_out[30]
  PIN rw0_rd_out[31]
    DIRECTION OUTPUT ;
    USE SIGNAL ;
    SHAPE ABUTMENT ;
    PORT
      LAYER M3_m ;
      RECT 0 294.035 0.07 294.105 ;
    END
  END rw0_rd_out[31]
  PIN rw0_rd_out[32]
    DIRECTION OUTPUT ;
    USE SIGNAL ;
    SHAPE ABUTMENT ;
    PORT
      LAYER M3_m ;
      RECT 0 295.715 0.07 295.785 ;
    END
  END rw0_rd_out[32]
  PIN rw0_rd_out[33]
    DIRECTION OUTPUT ;
    USE SIGNAL ;
    SHAPE ABUTMENT ;
    PORT
      LAYER M3_m ;
      RECT 0 297.395 0.07 297.465 ;
    END
  END rw0_rd_out[33]
  PIN rw0_rd_out[34]
    DIRECTION OUTPUT ;
    USE SIGNAL ;
    SHAPE ABUTMENT ;
    PORT
      LAYER M3_m ;
      RECT 0 299.075 0.07 299.145 ;
    END
  END rw0_rd_out[34]
  PIN rw0_rd_out[35]
    DIRECTION OUTPUT ;
    USE SIGNAL ;
    SHAPE ABUTMENT ;
    PORT
      LAYER M3_m ;
      RECT 0 300.755 0.07 300.825 ;
    END
  END rw0_rd_out[35]
  PIN rw0_rd_out[36]
    DIRECTION OUTPUT ;
    USE SIGNAL ;
    SHAPE ABUTMENT ;
    PORT
      LAYER M3_m ;
      RECT 0 302.435 0.07 302.505 ;
    END
  END rw0_rd_out[36]
  PIN rw0_rd_out[37]
    DIRECTION OUTPUT ;
    USE SIGNAL ;
    SHAPE ABUTMENT ;
    PORT
      LAYER M3_m ;
      RECT 0 304.115 0.07 304.185 ;
    END
  END rw0_rd_out[37]
  PIN rw0_rd_out[38]
    DIRECTION OUTPUT ;
    USE SIGNAL ;
    SHAPE ABUTMENT ;
    PORT
      LAYER M3_m ;
      RECT 0 305.795 0.07 305.865 ;
    END
  END rw0_rd_out[38]
  PIN rw0_rd_out[39]
    DIRECTION OUTPUT ;
    USE SIGNAL ;
    SHAPE ABUTMENT ;
    PORT
      LAYER M3_m ;
      RECT 0 307.475 0.07 307.545 ;
    END
  END rw0_rd_out[39]
  PIN rw0_rd_out[40]
    DIRECTION OUTPUT ;
    USE SIGNAL ;
    SHAPE ABUTMENT ;
    PORT
      LAYER M3_m ;
      RECT 0 309.155 0.07 309.225 ;
    END
  END rw0_rd_out[40]
  PIN rw0_rd_out[41]
    DIRECTION OUTPUT ;
    USE SIGNAL ;
    SHAPE ABUTMENT ;
    PORT
      LAYER M3_m ;
      RECT 0 310.835 0.07 310.905 ;
    END
  END rw0_rd_out[41]
  PIN rw0_rd_out[42]
    DIRECTION OUTPUT ;
    USE SIGNAL ;
    SHAPE ABUTMENT ;
    PORT
      LAYER M3_m ;
      RECT 0 312.515 0.07 312.585 ;
    END
  END rw0_rd_out[42]
  PIN rw0_rd_out[43]
    DIRECTION OUTPUT ;
    USE SIGNAL ;
    SHAPE ABUTMENT ;
    PORT
      LAYER M3_m ;
      RECT 0 314.195 0.07 314.265 ;
    END
  END rw0_rd_out[43]
  PIN rw0_rd_out[44]
    DIRECTION OUTPUT ;
    USE SIGNAL ;
    SHAPE ABUTMENT ;
    PORT
      LAYER M3_m ;
      RECT 0 315.875 0.07 315.945 ;
    END
  END rw0_rd_out[44]
  PIN rw0_rd_out[45]
    DIRECTION OUTPUT ;
    USE SIGNAL ;
    SHAPE ABUTMENT ;
    PORT
      LAYER M3_m ;
      RECT 0 317.555 0.07 317.625 ;
    END
  END rw0_rd_out[45]
  PIN rw0_rd_out[46]
    DIRECTION OUTPUT ;
    USE SIGNAL ;
    SHAPE ABUTMENT ;
    PORT
      LAYER M3_m ;
      RECT 0 319.235 0.07 319.305 ;
    END
  END rw0_rd_out[46]
  PIN rw0_rd_out[47]
    DIRECTION OUTPUT ;
    USE SIGNAL ;
    SHAPE ABUTMENT ;
    PORT
      LAYER M3_m ;
      RECT 0 320.915 0.07 320.985 ;
    END
  END rw0_rd_out[47]
  PIN rw0_rd_out[48]
    DIRECTION OUTPUT ;
    USE SIGNAL ;
    SHAPE ABUTMENT ;
    PORT
      LAYER M3_m ;
      RECT 0 322.595 0.07 322.665 ;
    END
  END rw0_rd_out[48]
  PIN rw0_rd_out[49]
    DIRECTION OUTPUT ;
    USE SIGNAL ;
    SHAPE ABUTMENT ;
    PORT
      LAYER M3_m ;
      RECT 0 324.275 0.07 324.345 ;
    END
  END rw0_rd_out[49]
  PIN rw0_rd_out[50]
    DIRECTION OUTPUT ;
    USE SIGNAL ;
    SHAPE ABUTMENT ;
    PORT
      LAYER M3_m ;
      RECT 0 325.955 0.07 326.025 ;
    END
  END rw0_rd_out[50]
  PIN rw0_rd_out[51]
    DIRECTION OUTPUT ;
    USE SIGNAL ;
    SHAPE ABUTMENT ;
    PORT
      LAYER M3_m ;
      RECT 0 327.635 0.07 327.705 ;
    END
  END rw0_rd_out[51]
  PIN rw0_rd_out[52]
    DIRECTION OUTPUT ;
    USE SIGNAL ;
    SHAPE ABUTMENT ;
    PORT
      LAYER M3_m ;
      RECT 0 329.315 0.07 329.385 ;
    END
  END rw0_rd_out[52]
  PIN rw0_rd_out[53]
    DIRECTION OUTPUT ;
    USE SIGNAL ;
    SHAPE ABUTMENT ;
    PORT
      LAYER M3_m ;
      RECT 0 330.995 0.07 331.065 ;
    END
  END rw0_rd_out[53]
  PIN rw0_rd_out[54]
    DIRECTION OUTPUT ;
    USE SIGNAL ;
    SHAPE ABUTMENT ;
    PORT
      LAYER M3_m ;
      RECT 0 332.675 0.07 332.745 ;
    END
  END rw0_rd_out[54]
  PIN rw0_rd_out[55]
    DIRECTION OUTPUT ;
    USE SIGNAL ;
    SHAPE ABUTMENT ;
    PORT
      LAYER M3_m ;
      RECT 0 334.355 0.07 334.425 ;
    END
  END rw0_rd_out[55]
  PIN rw0_rd_out[56]
    DIRECTION OUTPUT ;
    USE SIGNAL ;
    SHAPE ABUTMENT ;
    PORT
      LAYER M3_m ;
      RECT 0 336.035 0.07 336.105 ;
    END
  END rw0_rd_out[56]
  PIN rw0_rd_out[57]
    DIRECTION OUTPUT ;
    USE SIGNAL ;
    SHAPE ABUTMENT ;
    PORT
      LAYER M3_m ;
      RECT 0 337.715 0.07 337.785 ;
    END
  END rw0_rd_out[57]
  PIN rw0_rd_out[58]
    DIRECTION OUTPUT ;
    USE SIGNAL ;
    SHAPE ABUTMENT ;
    PORT
      LAYER M3_m ;
      RECT 0 339.395 0.07 339.465 ;
    END
  END rw0_rd_out[58]
  PIN rw0_rd_out[59]
    DIRECTION OUTPUT ;
    USE SIGNAL ;
    SHAPE ABUTMENT ;
    PORT
      LAYER M3_m ;
      RECT 0 341.075 0.07 341.145 ;
    END
  END rw0_rd_out[59]
  PIN rw0_rd_out[60]
    DIRECTION OUTPUT ;
    USE SIGNAL ;
    SHAPE ABUTMENT ;
    PORT
      LAYER M3_m ;
      RECT 0 342.755 0.07 342.825 ;
    END
  END rw0_rd_out[60]
  PIN rw0_rd_out[61]
    DIRECTION OUTPUT ;
    USE SIGNAL ;
    SHAPE ABUTMENT ;
    PORT
      LAYER M3_m ;
      RECT 0 344.435 0.07 344.505 ;
    END
  END rw0_rd_out[61]
  PIN rw0_rd_out[62]
    DIRECTION OUTPUT ;
    USE SIGNAL ;
    SHAPE ABUTMENT ;
    PORT
      LAYER M3_m ;
      RECT 0 346.115 0.07 346.185 ;
    END
  END rw0_rd_out[62]
  PIN rw0_rd_out[63]
    DIRECTION OUTPUT ;
    USE SIGNAL ;
    SHAPE ABUTMENT ;
    PORT
      LAYER M3_m ;
      RECT 0 347.795 0.07 347.865 ;
    END
  END rw0_rd_out[63]
  PIN rw0_rd_out[64]
    DIRECTION OUTPUT ;
    USE SIGNAL ;
    SHAPE ABUTMENT ;
    PORT
      LAYER M3_m ;
      RECT 0 349.475 0.07 349.545 ;
    END
  END rw0_rd_out[64]
  PIN rw0_rd_out[65]
    DIRECTION OUTPUT ;
    USE SIGNAL ;
    SHAPE ABUTMENT ;
    PORT
      LAYER M3_m ;
      RECT 0 351.155 0.07 351.225 ;
    END
  END rw0_rd_out[65]
  PIN rw0_rd_out[66]
    DIRECTION OUTPUT ;
    USE SIGNAL ;
    SHAPE ABUTMENT ;
    PORT
      LAYER M3_m ;
      RECT 0 352.835 0.07 352.905 ;
    END
  END rw0_rd_out[66]
  PIN rw0_rd_out[67]
    DIRECTION OUTPUT ;
    USE SIGNAL ;
    SHAPE ABUTMENT ;
    PORT
      LAYER M3_m ;
      RECT 0 354.515 0.07 354.585 ;
    END
  END rw0_rd_out[67]
  PIN rw0_rd_out[68]
    DIRECTION OUTPUT ;
    USE SIGNAL ;
    SHAPE ABUTMENT ;
    PORT
      LAYER M3_m ;
      RECT 0 356.195 0.07 356.265 ;
    END
  END rw0_rd_out[68]
  PIN rw0_rd_out[69]
    DIRECTION OUTPUT ;
    USE SIGNAL ;
    SHAPE ABUTMENT ;
    PORT
      LAYER M3_m ;
      RECT 0 357.875 0.07 357.945 ;
    END
  END rw0_rd_out[69]
  PIN rw0_rd_out[70]
    DIRECTION OUTPUT ;
    USE SIGNAL ;
    SHAPE ABUTMENT ;
    PORT
      LAYER M3_m ;
      RECT 0 359.555 0.07 359.625 ;
    END
  END rw0_rd_out[70]
  PIN rw0_rd_out[71]
    DIRECTION OUTPUT ;
    USE SIGNAL ;
    SHAPE ABUTMENT ;
    PORT
      LAYER M3_m ;
      RECT 0 361.235 0.07 361.305 ;
    END
  END rw0_rd_out[71]
  PIN rw0_rd_out[72]
    DIRECTION OUTPUT ;
    USE SIGNAL ;
    SHAPE ABUTMENT ;
    PORT
      LAYER M3_m ;
      RECT 0 362.915 0.07 362.985 ;
    END
  END rw0_rd_out[72]
  PIN rw0_rd_out[73]
    DIRECTION OUTPUT ;
    USE SIGNAL ;
    SHAPE ABUTMENT ;
    PORT
      LAYER M3_m ;
      RECT 0 364.595 0.07 364.665 ;
    END
  END rw0_rd_out[73]
  PIN rw0_rd_out[74]
    DIRECTION OUTPUT ;
    USE SIGNAL ;
    SHAPE ABUTMENT ;
    PORT
      LAYER M3_m ;
      RECT 0 366.275 0.07 366.345 ;
    END
  END rw0_rd_out[74]
  PIN rw0_rd_out[75]
    DIRECTION OUTPUT ;
    USE SIGNAL ;
    SHAPE ABUTMENT ;
    PORT
      LAYER M3_m ;
      RECT 0 367.955 0.07 368.025 ;
    END
  END rw0_rd_out[75]
  PIN rw0_rd_out[76]
    DIRECTION OUTPUT ;
    USE SIGNAL ;
    SHAPE ABUTMENT ;
    PORT
      LAYER M3_m ;
      RECT 0 369.635 0.07 369.705 ;
    END
  END rw0_rd_out[76]
  PIN rw0_rd_out[77]
    DIRECTION OUTPUT ;
    USE SIGNAL ;
    SHAPE ABUTMENT ;
    PORT
      LAYER M3_m ;
      RECT 0 371.315 0.07 371.385 ;
    END
  END rw0_rd_out[77]
  PIN rw0_rd_out[78]
    DIRECTION OUTPUT ;
    USE SIGNAL ;
    SHAPE ABUTMENT ;
    PORT
      LAYER M3_m ;
      RECT 0 372.995 0.07 373.065 ;
    END
  END rw0_rd_out[78]
  PIN rw0_rd_out[79]
    DIRECTION OUTPUT ;
    USE SIGNAL ;
    SHAPE ABUTMENT ;
    PORT
      LAYER M3_m ;
      RECT 0 374.675 0.07 374.745 ;
    END
  END rw0_rd_out[79]
  PIN rw0_rd_out[80]
    DIRECTION OUTPUT ;
    USE SIGNAL ;
    SHAPE ABUTMENT ;
    PORT
      LAYER M3_m ;
      RECT 0 376.355 0.07 376.425 ;
    END
  END rw0_rd_out[80]
  PIN rw0_rd_out[81]
    DIRECTION OUTPUT ;
    USE SIGNAL ;
    SHAPE ABUTMENT ;
    PORT
      LAYER M3_m ;
      RECT 0 378.035 0.07 378.105 ;
    END
  END rw0_rd_out[81]
  PIN rw0_rd_out[82]
    DIRECTION OUTPUT ;
    USE SIGNAL ;
    SHAPE ABUTMENT ;
    PORT
      LAYER M3_m ;
      RECT 0 379.715 0.07 379.785 ;
    END
  END rw0_rd_out[82]
  PIN rw0_rd_out[83]
    DIRECTION OUTPUT ;
    USE SIGNAL ;
    SHAPE ABUTMENT ;
    PORT
      LAYER M3_m ;
      RECT 0 381.395 0.07 381.465 ;
    END
  END rw0_rd_out[83]
  PIN rw0_rd_out[84]
    DIRECTION OUTPUT ;
    USE SIGNAL ;
    SHAPE ABUTMENT ;
    PORT
      LAYER M3_m ;
      RECT 0 383.075 0.07 383.145 ;
    END
  END rw0_rd_out[84]
  PIN rw0_rd_out[85]
    DIRECTION OUTPUT ;
    USE SIGNAL ;
    SHAPE ABUTMENT ;
    PORT
      LAYER M3_m ;
      RECT 0 384.755 0.07 384.825 ;
    END
  END rw0_rd_out[85]
  PIN rw0_rd_out[86]
    DIRECTION OUTPUT ;
    USE SIGNAL ;
    SHAPE ABUTMENT ;
    PORT
      LAYER M3_m ;
      RECT 0 386.435 0.07 386.505 ;
    END
  END rw0_rd_out[86]
  PIN rw0_rd_out[87]
    DIRECTION OUTPUT ;
    USE SIGNAL ;
    SHAPE ABUTMENT ;
    PORT
      LAYER M3_m ;
      RECT 0 388.115 0.07 388.185 ;
    END
  END rw0_rd_out[87]
  PIN rw0_rd_out[88]
    DIRECTION OUTPUT ;
    USE SIGNAL ;
    SHAPE ABUTMENT ;
    PORT
      LAYER M3_m ;
      RECT 0 389.795 0.07 389.865 ;
    END
  END rw0_rd_out[88]
  PIN rw0_rd_out[89]
    DIRECTION OUTPUT ;
    USE SIGNAL ;
    SHAPE ABUTMENT ;
    PORT
      LAYER M3_m ;
      RECT 0 391.475 0.07 391.545 ;
    END
  END rw0_rd_out[89]
  PIN rw0_rd_out[90]
    DIRECTION OUTPUT ;
    USE SIGNAL ;
    SHAPE ABUTMENT ;
    PORT
      LAYER M3_m ;
      RECT 0 393.155 0.07 393.225 ;
    END
  END rw0_rd_out[90]
  PIN rw0_rd_out[91]
    DIRECTION OUTPUT ;
    USE SIGNAL ;
    SHAPE ABUTMENT ;
    PORT
      LAYER M3_m ;
      RECT 0 394.835 0.07 394.905 ;
    END
  END rw0_rd_out[91]
  PIN rw0_rd_out[92]
    DIRECTION OUTPUT ;
    USE SIGNAL ;
    SHAPE ABUTMENT ;
    PORT
      LAYER M3_m ;
      RECT 0 396.515 0.07 396.585 ;
    END
  END rw0_rd_out[92]
  PIN rw0_rd_out[93]
    DIRECTION OUTPUT ;
    USE SIGNAL ;
    SHAPE ABUTMENT ;
    PORT
      LAYER M3_m ;
      RECT 0 398.195 0.07 398.265 ;
    END
  END rw0_rd_out[93]
  PIN rw0_rd_out[94]
    DIRECTION OUTPUT ;
    USE SIGNAL ;
    SHAPE ABUTMENT ;
    PORT
      LAYER M3_m ;
      RECT 0 399.875 0.07 399.945 ;
    END
  END rw0_rd_out[94]
  PIN rw0_rd_out[95]
    DIRECTION OUTPUT ;
    USE SIGNAL ;
    SHAPE ABUTMENT ;
    PORT
      LAYER M3_m ;
      RECT 0 401.555 0.07 401.625 ;
    END
  END rw0_rd_out[95]
  PIN rw0_rd_out[96]
    DIRECTION OUTPUT ;
    USE SIGNAL ;
    SHAPE ABUTMENT ;
    PORT
      LAYER M3_m ;
      RECT 0 403.235 0.07 403.305 ;
    END
  END rw0_rd_out[96]
  PIN rw0_rd_out[97]
    DIRECTION OUTPUT ;
    USE SIGNAL ;
    SHAPE ABUTMENT ;
    PORT
      LAYER M3_m ;
      RECT 0 404.915 0.07 404.985 ;
    END
  END rw0_rd_out[97]
  PIN rw0_rd_out[98]
    DIRECTION OUTPUT ;
    USE SIGNAL ;
    SHAPE ABUTMENT ;
    PORT
      LAYER M3_m ;
      RECT 0 406.595 0.07 406.665 ;
    END
  END rw0_rd_out[98]
  PIN rw0_rd_out[99]
    DIRECTION OUTPUT ;
    USE SIGNAL ;
    SHAPE ABUTMENT ;
    PORT
      LAYER M3_m ;
      RECT 0 408.275 0.07 408.345 ;
    END
  END rw0_rd_out[99]
  PIN rw0_rd_out[100]
    DIRECTION OUTPUT ;
    USE SIGNAL ;
    SHAPE ABUTMENT ;
    PORT
      LAYER M3_m ;
      RECT 0 409.955 0.07 410.025 ;
    END
  END rw0_rd_out[100]
  PIN rw0_rd_out[101]
    DIRECTION OUTPUT ;
    USE SIGNAL ;
    SHAPE ABUTMENT ;
    PORT
      LAYER M3_m ;
      RECT 0 411.635 0.07 411.705 ;
    END
  END rw0_rd_out[101]
  PIN rw0_rd_out[102]
    DIRECTION OUTPUT ;
    USE SIGNAL ;
    SHAPE ABUTMENT ;
    PORT
      LAYER M3_m ;
      RECT 0 413.315 0.07 413.385 ;
    END
  END rw0_rd_out[102]
  PIN rw0_rd_out[103]
    DIRECTION OUTPUT ;
    USE SIGNAL ;
    SHAPE ABUTMENT ;
    PORT
      LAYER M3_m ;
      RECT 0 414.995 0.07 415.065 ;
    END
  END rw0_rd_out[103]
  PIN rw0_rd_out[104]
    DIRECTION OUTPUT ;
    USE SIGNAL ;
    SHAPE ABUTMENT ;
    PORT
      LAYER M3_m ;
      RECT 0 416.675 0.07 416.745 ;
    END
  END rw0_rd_out[104]
  PIN rw0_rd_out[105]
    DIRECTION OUTPUT ;
    USE SIGNAL ;
    SHAPE ABUTMENT ;
    PORT
      LAYER M3_m ;
      RECT 0 418.355 0.07 418.425 ;
    END
  END rw0_rd_out[105]
  PIN rw0_rd_out[106]
    DIRECTION OUTPUT ;
    USE SIGNAL ;
    SHAPE ABUTMENT ;
    PORT
      LAYER M3_m ;
      RECT 0 420.035 0.07 420.105 ;
    END
  END rw0_rd_out[106]
  PIN rw0_rd_out[107]
    DIRECTION OUTPUT ;
    USE SIGNAL ;
    SHAPE ABUTMENT ;
    PORT
      LAYER M3_m ;
      RECT 0 421.715 0.07 421.785 ;
    END
  END rw0_rd_out[107]
  PIN rw0_rd_out[108]
    DIRECTION OUTPUT ;
    USE SIGNAL ;
    SHAPE ABUTMENT ;
    PORT
      LAYER M3_m ;
      RECT 0 423.395 0.07 423.465 ;
    END
  END rw0_rd_out[108]
  PIN rw0_rd_out[109]
    DIRECTION OUTPUT ;
    USE SIGNAL ;
    SHAPE ABUTMENT ;
    PORT
      LAYER M3_m ;
      RECT 0 425.075 0.07 425.145 ;
    END
  END rw0_rd_out[109]
  PIN rw0_rd_out[110]
    DIRECTION OUTPUT ;
    USE SIGNAL ;
    SHAPE ABUTMENT ;
    PORT
      LAYER M3_m ;
      RECT 0 426.755 0.07 426.825 ;
    END
  END rw0_rd_out[110]
  PIN rw0_rd_out[111]
    DIRECTION OUTPUT ;
    USE SIGNAL ;
    SHAPE ABUTMENT ;
    PORT
      LAYER M3_m ;
      RECT 0 428.435 0.07 428.505 ;
    END
  END rw0_rd_out[111]
  PIN rw0_rd_out[112]
    DIRECTION OUTPUT ;
    USE SIGNAL ;
    SHAPE ABUTMENT ;
    PORT
      LAYER M3_m ;
      RECT 0 430.115 0.07 430.185 ;
    END
  END rw0_rd_out[112]
  PIN rw0_rd_out[113]
    DIRECTION OUTPUT ;
    USE SIGNAL ;
    SHAPE ABUTMENT ;
    PORT
      LAYER M3_m ;
      RECT 0 431.795 0.07 431.865 ;
    END
  END rw0_rd_out[113]
  PIN rw0_rd_out[114]
    DIRECTION OUTPUT ;
    USE SIGNAL ;
    SHAPE ABUTMENT ;
    PORT
      LAYER M3_m ;
      RECT 0 433.475 0.07 433.545 ;
    END
  END rw0_rd_out[114]
  PIN rw0_rd_out[115]
    DIRECTION OUTPUT ;
    USE SIGNAL ;
    SHAPE ABUTMENT ;
    PORT
      LAYER M3_m ;
      RECT 0 435.155 0.07 435.225 ;
    END
  END rw0_rd_out[115]
  PIN rw0_rd_out[116]
    DIRECTION OUTPUT ;
    USE SIGNAL ;
    SHAPE ABUTMENT ;
    PORT
      LAYER M3_m ;
      RECT 0 436.835 0.07 436.905 ;
    END
  END rw0_rd_out[116]
  PIN rw0_rd_out[117]
    DIRECTION OUTPUT ;
    USE SIGNAL ;
    SHAPE ABUTMENT ;
    PORT
      LAYER M3_m ;
      RECT 0 438.515 0.07 438.585 ;
    END
  END rw0_rd_out[117]
  PIN rw0_rd_out[118]
    DIRECTION OUTPUT ;
    USE SIGNAL ;
    SHAPE ABUTMENT ;
    PORT
      LAYER M3_m ;
      RECT 0 440.195 0.07 440.265 ;
    END
  END rw0_rd_out[118]
  PIN rw0_rd_out[119]
    DIRECTION OUTPUT ;
    USE SIGNAL ;
    SHAPE ABUTMENT ;
    PORT
      LAYER M3_m ;
      RECT 0 441.875 0.07 441.945 ;
    END
  END rw0_rd_out[119]
  PIN rw0_rd_out[120]
    DIRECTION OUTPUT ;
    USE SIGNAL ;
    SHAPE ABUTMENT ;
    PORT
      LAYER M3_m ;
      RECT 0 443.555 0.07 443.625 ;
    END
  END rw0_rd_out[120]
  PIN rw0_rd_out[121]
    DIRECTION OUTPUT ;
    USE SIGNAL ;
    SHAPE ABUTMENT ;
    PORT
      LAYER M3_m ;
      RECT 0 445.235 0.07 445.305 ;
    END
  END rw0_rd_out[121]
  PIN rw0_rd_out[122]
    DIRECTION OUTPUT ;
    USE SIGNAL ;
    SHAPE ABUTMENT ;
    PORT
      LAYER M3_m ;
      RECT 0 446.915 0.07 446.985 ;
    END
  END rw0_rd_out[122]
  PIN rw0_rd_out[123]
    DIRECTION OUTPUT ;
    USE SIGNAL ;
    SHAPE ABUTMENT ;
    PORT
      LAYER M3_m ;
      RECT 0 448.595 0.07 448.665 ;
    END
  END rw0_rd_out[123]
  PIN rw0_rd_out[124]
    DIRECTION OUTPUT ;
    USE SIGNAL ;
    SHAPE ABUTMENT ;
    PORT
      LAYER M3_m ;
      RECT 0 450.275 0.07 450.345 ;
    END
  END rw0_rd_out[124]
  PIN rw0_rd_out[125]
    DIRECTION OUTPUT ;
    USE SIGNAL ;
    SHAPE ABUTMENT ;
    PORT
      LAYER M3_m ;
      RECT 0 451.955 0.07 452.025 ;
    END
  END rw0_rd_out[125]
  PIN rw0_rd_out[126]
    DIRECTION OUTPUT ;
    USE SIGNAL ;
    SHAPE ABUTMENT ;
    PORT
      LAYER M3_m ;
      RECT 0 453.635 0.07 453.705 ;
    END
  END rw0_rd_out[126]
  PIN rw0_rd_out[127]
    DIRECTION OUTPUT ;
    USE SIGNAL ;
    SHAPE ABUTMENT ;
    PORT
      LAYER M3_m ;
      RECT 0 455.315 0.07 455.385 ;
    END
  END rw0_rd_out[127]
  PIN rw0_rd_out[128]
    DIRECTION OUTPUT ;
    USE SIGNAL ;
    SHAPE ABUTMENT ;
    PORT
      LAYER M3_m ;
      RECT 0 456.995 0.07 457.065 ;
    END
  END rw0_rd_out[128]
  PIN rw0_rd_out[129]
    DIRECTION OUTPUT ;
    USE SIGNAL ;
    SHAPE ABUTMENT ;
    PORT
      LAYER M3_m ;
      RECT 0 458.675 0.07 458.745 ;
    END
  END rw0_rd_out[129]
  PIN rw0_rd_out[130]
    DIRECTION OUTPUT ;
    USE SIGNAL ;
    SHAPE ABUTMENT ;
    PORT
      LAYER M3_m ;
      RECT 0 460.355 0.07 460.425 ;
    END
  END rw0_rd_out[130]
  PIN rw0_rd_out[131]
    DIRECTION OUTPUT ;
    USE SIGNAL ;
    SHAPE ABUTMENT ;
    PORT
      LAYER M3_m ;
      RECT 0 462.035 0.07 462.105 ;
    END
  END rw0_rd_out[131]
  PIN rw0_rd_out[132]
    DIRECTION OUTPUT ;
    USE SIGNAL ;
    SHAPE ABUTMENT ;
    PORT
      LAYER M3_m ;
      RECT 0 463.715 0.07 463.785 ;
    END
  END rw0_rd_out[132]
  PIN rw0_rd_out[133]
    DIRECTION OUTPUT ;
    USE SIGNAL ;
    SHAPE ABUTMENT ;
    PORT
      LAYER M3_m ;
      RECT 0 465.395 0.07 465.465 ;
    END
  END rw0_rd_out[133]
  PIN rw0_rd_out[134]
    DIRECTION OUTPUT ;
    USE SIGNAL ;
    SHAPE ABUTMENT ;
    PORT
      LAYER M3_m ;
      RECT 0 467.075 0.07 467.145 ;
    END
  END rw0_rd_out[134]
  PIN rw0_rd_out[135]
    DIRECTION OUTPUT ;
    USE SIGNAL ;
    SHAPE ABUTMENT ;
    PORT
      LAYER M3_m ;
      RECT 0 468.755 0.07 468.825 ;
    END
  END rw0_rd_out[135]
  PIN rw0_addr_in[0]
    DIRECTION INPUT ;
    USE SIGNAL ;
    SHAPE ABUTMENT ;
    PORT
      LAYER M3_m ;
      RECT 0 470.435 0.07 470.505 ;
    END
  END rw0_addr_in[0]
  PIN rw0_addr_in[1]
    DIRECTION INPUT ;
    USE SIGNAL ;
    SHAPE ABUTMENT ;
    PORT
      LAYER M3_m ;
      RECT 0 472.115 0.07 472.185 ;
    END
  END rw0_addr_in[1]
  PIN rw0_addr_in[2]
    DIRECTION INPUT ;
    USE SIGNAL ;
    SHAPE ABUTMENT ;
    PORT
      LAYER M3_m ;
      RECT 0 473.795 0.07 473.865 ;
    END
  END rw0_addr_in[2]
  PIN rw0_addr_in[3]
    DIRECTION INPUT ;
    USE SIGNAL ;
    SHAPE ABUTMENT ;
    PORT
      LAYER M3_m ;
      RECT 0 475.475 0.07 475.545 ;
    END
  END rw0_addr_in[3]
  PIN rw0_addr_in[4]
    DIRECTION INPUT ;
    USE SIGNAL ;
    SHAPE ABUTMENT ;
    PORT
      LAYER M3_m ;
      RECT 0 477.155 0.07 477.225 ;
    END
  END rw0_addr_in[4]
  PIN rw0_addr_in[5]
    DIRECTION INPUT ;
    USE SIGNAL ;
    SHAPE ABUTMENT ;
    PORT
      LAYER M3_m ;
      RECT 0 478.835 0.07 478.905 ;
    END
  END rw0_addr_in[5]
  PIN rw0_addr_in[6]
    DIRECTION INPUT ;
    USE SIGNAL ;
    SHAPE ABUTMENT ;
    PORT
      LAYER M3_m ;
      RECT 0 480.515 0.07 480.585 ;
    END
  END rw0_addr_in[6]
  PIN rw0_addr_in[7]
    DIRECTION INPUT ;
    USE SIGNAL ;
    SHAPE ABUTMENT ;
    PORT
      LAYER M3_m ;
      RECT 0 482.195 0.07 482.265 ;
    END
  END rw0_addr_in[7]
  PIN rw0_addr_in[8]
    DIRECTION INPUT ;
    USE SIGNAL ;
    SHAPE ABUTMENT ;
    PORT
      LAYER M3_m ;
      RECT 0 483.875 0.07 483.945 ;
    END
  END rw0_addr_in[8]
  PIN rw0_addr_in[9]
    DIRECTION INPUT ;
    USE SIGNAL ;
    SHAPE ABUTMENT ;
    PORT
      LAYER M3_m ;
      RECT 0 485.555 0.07 485.625 ;
    END
  END rw0_addr_in[9]
  PIN rw0_we_in
    DIRECTION INPUT ;
    USE SIGNAL ;
    SHAPE ABUTMENT ;
    PORT
      LAYER M3_m ;
      RECT 0 487.235 0.07 487.305 ;
    END
  END rw0_we_in
  PIN rw0_ce_in
    DIRECTION INPUT ;
    USE SIGNAL ;
    SHAPE ABUTMENT ;
    PORT
      LAYER M3_m ;
      RECT 0 488.915 0.07 488.985 ;
    END
  END rw0_ce_in
  PIN rw0_clk
    DIRECTION INPUT ;
    USE SIGNAL ;
    SHAPE ABUTMENT ;
    PORT
      LAYER M3_m ;
      RECT 0 490.595 0.07 490.665 ;
    END
  END rw0_clk
  PIN VSS
    DIRECTION INOUT ;
    USE GROUND ;
    PORT
      LAYER M4_m ;
      RECT 1 0.84 1.28 524.16 ;
      RECT 3.24 0.84 3.52 524.16 ;
      RECT 5.48 0.84 5.76 524.16 ;
      RECT 7.72 0.84 8 524.16 ;
      RECT 9.96 0.84 10.24 524.16 ;
      RECT 12.2 0.84 12.48 524.16 ;
      RECT 14.44 0.84 14.72 524.16 ;
      RECT 16.68 0.84 16.96 524.16 ;
      RECT 18.92 0.84 19.2 524.16 ;
      RECT 21.16 0.84 21.44 524.16 ;
      RECT 23.4 0.84 23.68 524.16 ;
      RECT 25.64 0.84 25.92 524.16 ;
      RECT 27.88 0.84 28.16 524.16 ;
      RECT 30.12 0.84 30.4 524.16 ;
      RECT 32.36 0.84 32.64 524.16 ;
      RECT 34.6 0.84 34.88 524.16 ;
      RECT 36.84 0.84 37.12 524.16 ;
      RECT 39.08 0.84 39.36 524.16 ;
      RECT 41.32 0.84 41.6 524.16 ;
      RECT 43.56 0.84 43.84 524.16 ;
      RECT 45.8 0.84 46.08 524.16 ;
      RECT 48.04 0.84 48.32 524.16 ;
      RECT 50.28 0.84 50.56 524.16 ;
      RECT 52.52 0.84 52.8 524.16 ;
      RECT 54.76 0.84 55.04 524.16 ;
      RECT 57 0.84 57.28 524.16 ;
      RECT 59.24 0.84 59.52 524.16 ;
      RECT 61.48 0.84 61.76 524.16 ;
      RECT 63.72 0.84 64 524.16 ;
      RECT 65.96 0.84 66.24 524.16 ;
      RECT 68.2 0.84 68.48 524.16 ;
      RECT 70.44 0.84 70.72 524.16 ;
      RECT 72.68 0.84 72.96 524.16 ;
      RECT 74.92 0.84 75.2 524.16 ;
      RECT 77.16 0.84 77.44 524.16 ;
      RECT 79.4 0.84 79.68 524.16 ;
      RECT 81.64 0.84 81.92 524.16 ;
      RECT 83.88 0.84 84.16 524.16 ;
      RECT 86.12 0.84 86.4 524.16 ;
      RECT 88.36 0.84 88.64 524.16 ;
      RECT 90.6 0.84 90.88 524.16 ;
      RECT 92.84 0.84 93.12 524.16 ;
      RECT 95.08 0.84 95.36 524.16 ;
      RECT 97.32 0.84 97.6 524.16 ;
      RECT 99.56 0.84 99.84 524.16 ;
      RECT 101.8 0.84 102.08 524.16 ;
      RECT 104.04 0.84 104.32 524.16 ;
      RECT 106.28 0.84 106.56 524.16 ;
      RECT 108.52 0.84 108.8 524.16 ;
      RECT 110.76 0.84 111.04 524.16 ;
      RECT 113 0.84 113.28 524.16 ;
      RECT 115.24 0.84 115.52 524.16 ;
      RECT 117.48 0.84 117.76 524.16 ;
      RECT 119.72 0.84 120 524.16 ;
      RECT 121.96 0.84 122.24 524.16 ;
      RECT 124.2 0.84 124.48 524.16 ;
      RECT 126.44 0.84 126.72 524.16 ;
      RECT 128.68 0.84 128.96 524.16 ;
      RECT 130.92 0.84 131.2 524.16 ;
      RECT 133.16 0.84 133.44 524.16 ;
      RECT 135.4 0.84 135.68 524.16 ;
      RECT 137.64 0.84 137.92 524.16 ;
      RECT 139.88 0.84 140.16 524.16 ;
      RECT 142.12 0.84 142.4 524.16 ;
      RECT 144.36 0.84 144.64 524.16 ;
      RECT 146.6 0.84 146.88 524.16 ;
      RECT 148.84 0.84 149.12 524.16 ;
      RECT 151.08 0.84 151.36 524.16 ;
      RECT 153.32 0.84 153.6 524.16 ;
      RECT 155.56 0.84 155.84 524.16 ;
      RECT 157.8 0.84 158.08 524.16 ;
      RECT 160.04 0.84 160.32 524.16 ;
      RECT 162.28 0.84 162.56 524.16 ;
      RECT 164.52 0.84 164.8 524.16 ;
      RECT 166.76 0.84 167.04 524.16 ;
      RECT 169 0.84 169.28 524.16 ;
      RECT 171.24 0.84 171.52 524.16 ;
      RECT 173.48 0.84 173.76 524.16 ;
      RECT 175.72 0.84 176 524.16 ;
      RECT 177.96 0.84 178.24 524.16 ;
      RECT 180.2 0.84 180.48 524.16 ;
      RECT 182.44 0.84 182.72 524.16 ;
      RECT 184.68 0.84 184.96 524.16 ;
      RECT 186.92 0.84 187.2 524.16 ;
      RECT 189.16 0.84 189.44 524.16 ;
      RECT 191.4 0.84 191.68 524.16 ;
      RECT 193.64 0.84 193.92 524.16 ;
      RECT 195.88 0.84 196.16 524.16 ;
      RECT 198.12 0.84 198.4 524.16 ;
      RECT 200.36 0.84 200.64 524.16 ;
      RECT 202.6 0.84 202.88 524.16 ;
      RECT 204.84 0.84 205.12 524.16 ;
      RECT 207.08 0.84 207.36 524.16 ;
      RECT 209.32 0.84 209.6 524.16 ;
      RECT 211.56 0.84 211.84 524.16 ;
      RECT 213.8 0.84 214.08 524.16 ;
      RECT 216.04 0.84 216.32 524.16 ;
      RECT 218.28 0.84 218.56 524.16 ;
      RECT 220.52 0.84 220.8 524.16 ;
      RECT 222.76 0.84 223.04 524.16 ;
      RECT 225 0.84 225.28 524.16 ;
      RECT 227.24 0.84 227.52 524.16 ;
      RECT 229.48 0.84 229.76 524.16 ;
      RECT 231.72 0.84 232 524.16 ;
      RECT 233.96 0.84 234.24 524.16 ;
      RECT 236.2 0.84 236.48 524.16 ;
      RECT 238.44 0.84 238.72 524.16 ;
      RECT 240.68 0.84 240.96 524.16 ;
      RECT 242.92 0.84 243.2 524.16 ;
      RECT 245.16 0.84 245.44 524.16 ;
      RECT 247.4 0.84 247.68 524.16 ;
      RECT 249.64 0.84 249.92 524.16 ;
      RECT 251.88 0.84 252.16 524.16 ;
    END
  END VSS
  PIN VDD
    DIRECTION INOUT ;
    USE POWER ;
    PORT
      LAYER M4_m ;
      RECT 2.12 0.84 2.4 524.16 ;
      RECT 4.36 0.84 4.64 524.16 ;
      RECT 6.6 0.84 6.88 524.16 ;
      RECT 8.84 0.84 9.12 524.16 ;
      RECT 11.08 0.84 11.36 524.16 ;
      RECT 13.32 0.84 13.6 524.16 ;
      RECT 15.56 0.84 15.84 524.16 ;
      RECT 17.8 0.84 18.08 524.16 ;
      RECT 20.04 0.84 20.32 524.16 ;
      RECT 22.28 0.84 22.56 524.16 ;
      RECT 24.52 0.84 24.8 524.16 ;
      RECT 26.76 0.84 27.04 524.16 ;
      RECT 29 0.84 29.28 524.16 ;
      RECT 31.24 0.84 31.52 524.16 ;
      RECT 33.48 0.84 33.76 524.16 ;
      RECT 35.72 0.84 36 524.16 ;
      RECT 37.96 0.84 38.24 524.16 ;
      RECT 40.2 0.84 40.48 524.16 ;
      RECT 42.44 0.84 42.72 524.16 ;
      RECT 44.68 0.84 44.96 524.16 ;
      RECT 46.92 0.84 47.2 524.16 ;
      RECT 49.16 0.84 49.44 524.16 ;
      RECT 51.4 0.84 51.68 524.16 ;
      RECT 53.64 0.84 53.92 524.16 ;
      RECT 55.88 0.84 56.16 524.16 ;
      RECT 58.12 0.84 58.4 524.16 ;
      RECT 60.36 0.84 60.64 524.16 ;
      RECT 62.6 0.84 62.88 524.16 ;
      RECT 64.84 0.84 65.12 524.16 ;
      RECT 67.08 0.84 67.36 524.16 ;
      RECT 69.32 0.84 69.6 524.16 ;
      RECT 71.56 0.84 71.84 524.16 ;
      RECT 73.8 0.84 74.08 524.16 ;
      RECT 76.04 0.84 76.32 524.16 ;
      RECT 78.28 0.84 78.56 524.16 ;
      RECT 80.52 0.84 80.8 524.16 ;
      RECT 82.76 0.84 83.04 524.16 ;
      RECT 85 0.84 85.28 524.16 ;
      RECT 87.24 0.84 87.52 524.16 ;
      RECT 89.48 0.84 89.76 524.16 ;
      RECT 91.72 0.84 92 524.16 ;
      RECT 93.96 0.84 94.24 524.16 ;
      RECT 96.2 0.84 96.48 524.16 ;
      RECT 98.44 0.84 98.72 524.16 ;
      RECT 100.68 0.84 100.96 524.16 ;
      RECT 102.92 0.84 103.2 524.16 ;
      RECT 105.16 0.84 105.44 524.16 ;
      RECT 107.4 0.84 107.68 524.16 ;
      RECT 109.64 0.84 109.92 524.16 ;
      RECT 111.88 0.84 112.16 524.16 ;
      RECT 114.12 0.84 114.4 524.16 ;
      RECT 116.36 0.84 116.64 524.16 ;
      RECT 118.6 0.84 118.88 524.16 ;
      RECT 120.84 0.84 121.12 524.16 ;
      RECT 123.08 0.84 123.36 524.16 ;
      RECT 125.32 0.84 125.6 524.16 ;
      RECT 127.56 0.84 127.84 524.16 ;
      RECT 129.8 0.84 130.08 524.16 ;
      RECT 132.04 0.84 132.32 524.16 ;
      RECT 134.28 0.84 134.56 524.16 ;
      RECT 136.52 0.84 136.8 524.16 ;
      RECT 138.76 0.84 139.04 524.16 ;
      RECT 141 0.84 141.28 524.16 ;
      RECT 143.24 0.84 143.52 524.16 ;
      RECT 145.48 0.84 145.76 524.16 ;
      RECT 147.72 0.84 148 524.16 ;
      RECT 149.96 0.84 150.24 524.16 ;
      RECT 152.2 0.84 152.48 524.16 ;
      RECT 154.44 0.84 154.72 524.16 ;
      RECT 156.68 0.84 156.96 524.16 ;
      RECT 158.92 0.84 159.2 524.16 ;
      RECT 161.16 0.84 161.44 524.16 ;
      RECT 163.4 0.84 163.68 524.16 ;
      RECT 165.64 0.84 165.92 524.16 ;
      RECT 167.88 0.84 168.16 524.16 ;
      RECT 170.12 0.84 170.4 524.16 ;
      RECT 172.36 0.84 172.64 524.16 ;
      RECT 174.6 0.84 174.88 524.16 ;
      RECT 176.84 0.84 177.12 524.16 ;
      RECT 179.08 0.84 179.36 524.16 ;
      RECT 181.32 0.84 181.6 524.16 ;
      RECT 183.56 0.84 183.84 524.16 ;
      RECT 185.8 0.84 186.08 524.16 ;
      RECT 188.04 0.84 188.32 524.16 ;
      RECT 190.28 0.84 190.56 524.16 ;
      RECT 192.52 0.84 192.8 524.16 ;
      RECT 194.76 0.84 195.04 524.16 ;
      RECT 197 0.84 197.28 524.16 ;
      RECT 199.24 0.84 199.52 524.16 ;
      RECT 201.48 0.84 201.76 524.16 ;
      RECT 203.72 0.84 204 524.16 ;
      RECT 205.96 0.84 206.24 524.16 ;
      RECT 208.2 0.84 208.48 524.16 ;
      RECT 210.44 0.84 210.72 524.16 ;
      RECT 212.68 0.84 212.96 524.16 ;
      RECT 214.92 0.84 215.2 524.16 ;
      RECT 217.16 0.84 217.44 524.16 ;
      RECT 219.4 0.84 219.68 524.16 ;
      RECT 221.64 0.84 221.92 524.16 ;
      RECT 223.88 0.84 224.16 524.16 ;
      RECT 226.12 0.84 226.4 524.16 ;
      RECT 228.36 0.84 228.64 524.16 ;
      RECT 230.6 0.84 230.88 524.16 ;
      RECT 232.84 0.84 233.12 524.16 ;
      RECT 235.08 0.84 235.36 524.16 ;
      RECT 237.32 0.84 237.6 524.16 ;
      RECT 239.56 0.84 239.84 524.16 ;
      RECT 241.8 0.84 242.08 524.16 ;
      RECT 244.04 0.84 244.32 524.16 ;
      RECT 246.28 0.84 246.56 524.16 ;
      RECT 248.52 0.84 248.8 524.16 ;
      RECT 250.76 0.84 251.04 524.16 ;
      RECT 253 0.84 253.28 524.16 ;
    END
  END VDD
  OBS
    LAYER M1_m ;
    RECT 0 0 253.46 525 ;
    LAYER M2_m ;
    RECT 0 0 253.46 525 ;
  END
END ht45_rocketgemmini_cc_dir_ext_upper

END LIBRARY
